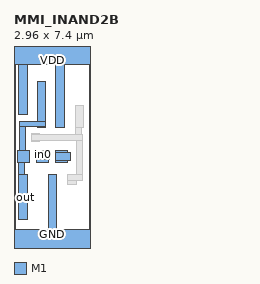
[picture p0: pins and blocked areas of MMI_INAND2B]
MACRO MMI_INAND2B
	CLASS CORE ;
	FOREIGN MMI_INAND2B 0 0 ;
	SIZE 2.96 BY 7.4 ;
	SYMMETRY X Y ;
	SITE CORE1 ;
	PIN out
		DIRECTION output ;
		USE SIGNAL ;
		PORT
			LAYER M1 ;
			RECT 0.9 4.71 1.24 6.235 ;
			LAYER M1 ;
			RECT 0.205 4.48 1.24 4.71 ;
			LAYER M1 ;
			RECT 0.205 3.555 0.435 4.48 ;
			LAYER M1 ;
			RECT 0.9 4.475 1.24 4.48 ;
			LAYER M1 ;
			RECT 0.145 3.105 0.595 3.555 ;
			LAYER M1 ;
			RECT 0.18 2.62 0.41 3.105 ;
			LAYER M1 ;
			RECT 0.18 0.86 0.52 2.62 ;
		END
		AntennaDiffArea 1.8768 ;
	END out
	PIN in1
		DIRECTION input ;
		USE SIGNAL ;
		PORT
			LAYER M1 ;
			RECT 1.625 3.495 2.075 3.555 ;
			LAYER M1 ;
			RECT 1.625 3.155 2.19 3.495 ;
			LAYER M1 ;
			RECT 1.625 3.105 2.075 3.155 ;
		END
		AntennaGateArea 0.2484 ;
	END in1
	PIN GND
		DIRECTION inout ;
		USE GROUND ;
		PORT
			LAYER M1 ;
			RECT 1.33 0.5 1.67 2.62 ;
			LAYER M1 ;
			RECT 0 -0.5 2.96 0.5 ;
		END
	END GND
	PIN VDD
		DIRECTION inout ;
		USE POWER ;
		PORT
			LAYER M1 ;
			RECT 0 6.9 2.96 7.9 ;
			LAYER M1 ;
			RECT 0.18 4.955 0.52 6.9 ;
			LAYER M1 ;
			RECT 1.62 4.475 1.96 6.9 ;
		END
	END VDD
	PIN in0
		DIRECTION input ;
		USE SIGNAL ;
		PORT
			LAYER M1 ;
			RECT 1.055 3.555 1.395 3.57 ;
			LAYER M1 ;
			RECT 0.885 3.23 1.395 3.555 ;
			LAYER M1 ;
			RECT 0.885 3.105 1.335 3.23 ;
		END
		AntennaGateArea 0.6624 ;
	END in0
	OBS
		LAYER M1 ;
		RECT 2.38 4.475 2.72 5.315 ;
		LAYER M1 ;
		RECT 0.665 4.175 1.005 4.24 ;
		LAYER M1 ;
		RECT 2.385 4.175 2.615 4.475 ;
		LAYER M1 ;
		RECT 0.665 3.945 2.65 4.175 ;
		LAYER M1 ;
		RECT 0.665 3.9 1.005 3.945 ;
		LAYER M1 ;
		RECT 2.42 2.62 2.65 3.945 ;
		LAYER M1 ;
		RECT 2.09 2.39 2.65 2.62 ;
		LAYER M1 ;
		RECT 2.09 2.24 2.43 2.39 ;
	END
END MMI_INAND2B
